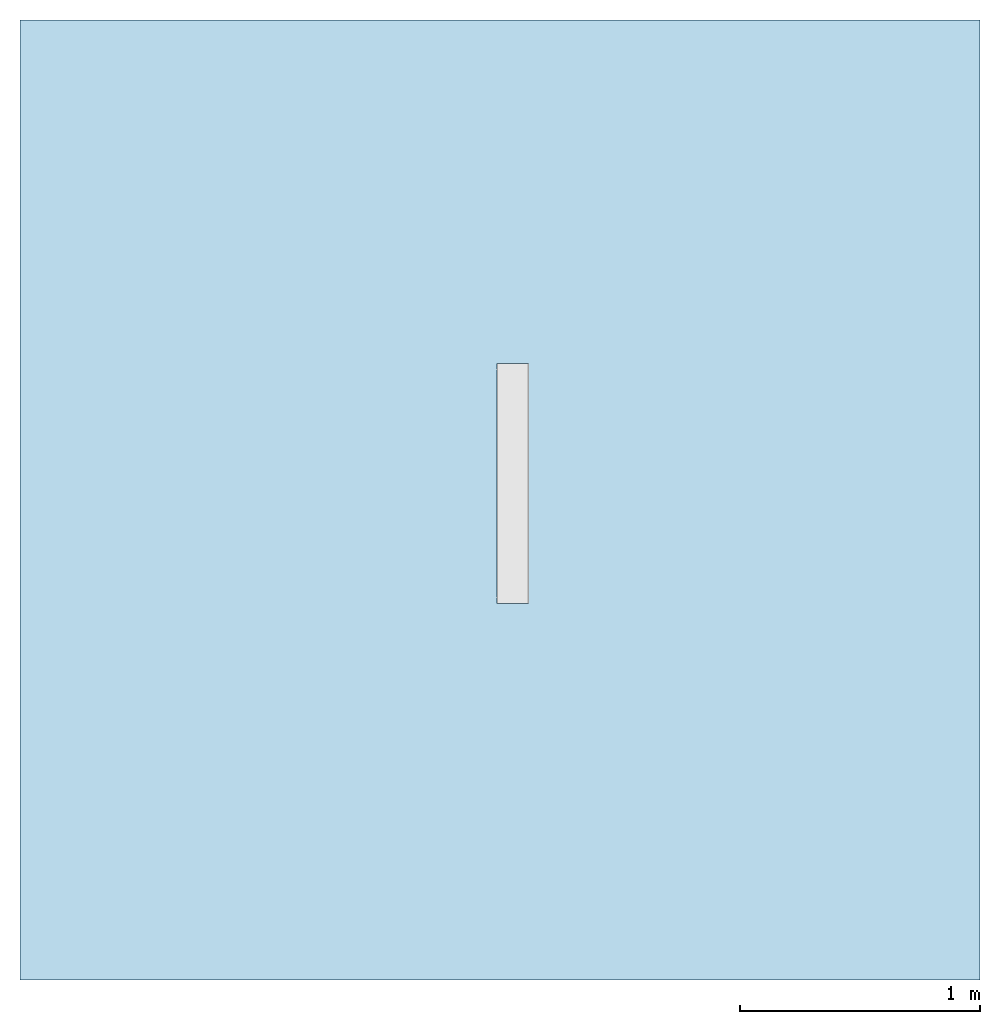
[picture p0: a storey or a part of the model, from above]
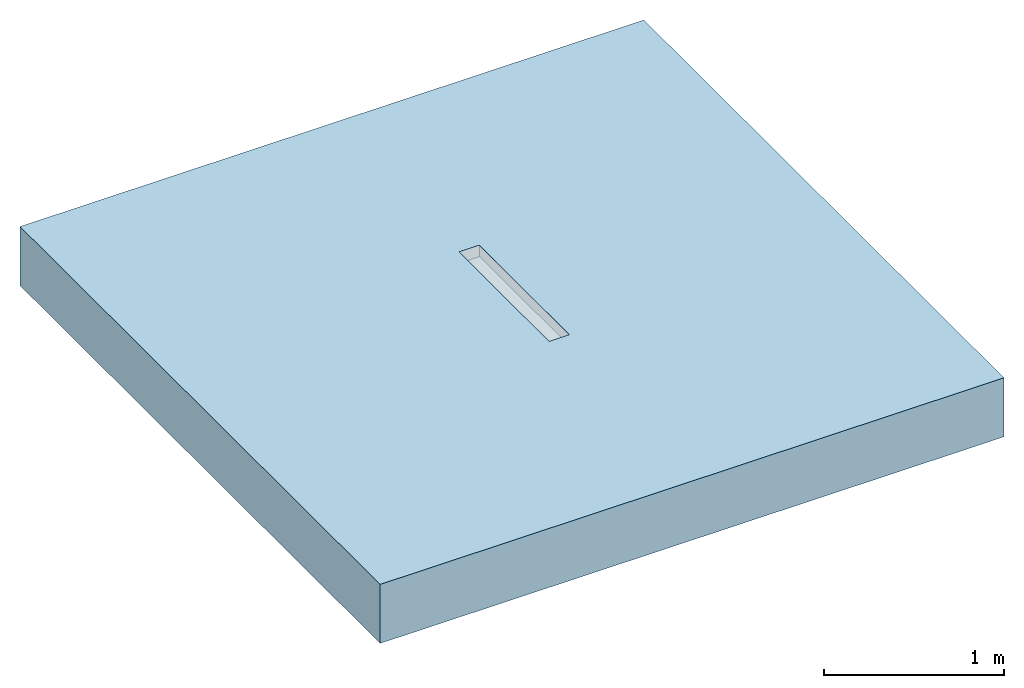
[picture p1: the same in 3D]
Properties of the parts of a building model (IFC2X3)

# File
Description: ViewDefinition [CoordinationView]
File name: Project Number
Time: 2014-06-06T14:49:13
Written by: The EXPRESS Data Manager Version 5.01.0100.02.64mod : 6 Jun 2012
Made in: 20130308_1515(x64) - Exporter 2014.0.2013.0308 - Default UI
Comment: STEP Physical File produced by: The EXPRESS Data Manager Version 5.01.0100.02.64mod : 6 Jun 2012 * Module: EDMstepFileFactory/EDMstandAlone * Creation date: Fri Jun 06 14:49:13 2014 * Host: IN-BLR-PC-0010 * Database: C:\Users\palleri\AppData\Local\Temp\{F6729BFF-8705-4B80-A60D-7009C70806BE}\ifc * Database version: 5507 * Database creation date: Fri Jun 06 14:49:11 2014 * Schema: IFC2X3 * Model: DataRepository.ifc * Model creation date: Fri Jun 06 14:49:12 2014 * Header model: DataRepository.ifc_HeaderModel * Header model creation date: Fri Jun 06 14:49:12 2014 * EDMuser: sdai-user * EDMgroup: sdai-group * License ID and type: 5605 : Permanent license. Expiry date: * EDMstepFileFactory options: 020000

# IfcProject, Project Number
LongName: Project Name; Phase: Project Status

# IfcSite, Default
RefLatitude: 42, 21, 30, 344238; RefLongitude: -71, -3, -35, -194702; RefElevation: 0 mm

# IfcBuilding
Pset_BuildingCommon - NumberOfStoreys: 1
Other - Project Address: ## Street City, State Zip; Project Number: Project Number; Project Issue Date: Issue Date; Client Name: Owner; Project Name: Project Name; Project Status: Project Status

# IfcBuildingStorey, Level 1
LongName: Level 1; Elevation: 0 mm
Constraints - Elevation Base: Project Base Point; Elevation: 0 mm
Graphics - Line Pattern: Center; Symbol: M_Level Head - Circle: M_Level Head - Circle; Line Weight: 1; Symbol at End 2 Default: yes; Symbol at End 1 Default: no; Color: 0
Identity Data - Building Story: yes; Structural: no; Name: Level 1
Dimensions - Computation Height: 0 mm

# IfcFlowTerminal: 36943 - Adjustable Channel - Shallow Section - 1000mm LG - Invert Depth 55/77mm, ACO Freedeck Adjustable Height Channel Shallow Section Stainless Steel:36943 - Adjustable Channel - Shallow Section - 1000mm LG - Invert Depth 55/77mm:317948
In: Level 1
Material: Stainless Steel Grade 304
Identity Data - Mark: 29; E-mail Technical: abdtechnical@aco.co.uk; E-mail Sales: abdcommercial@aco.co.uk; Fax: +44 (0)1462 851490; Address: ACO Business Centre, Caxton Road, Bedford, MK41 0LF; Watermark1: This file is the property of ACO Technologies PLC; Telephone: +44 (0)1462 816666; Manufacturer: ACO Building Drainage; Watermark2: This file is water marked and users are prohibited to reproduce, adapt, distribute this information; Watermarked With: BIM Manager Premium Suite; Website: www.acobd.com; Watermarked By: www.acobd.com
Construction - 36954 - Grating - Plain Mesh - Stainless Steel 304 - 500mm long: no; End Plate Invert 1: no; 36955 - Grating - Plain Mesh - Stainless Steel 304 - 1000mm long: yes; 00272 - Grating - Slotted Grating - Stainless Steel 304 - 1000mm long: no; 00273 - Grating - Slotted Grating - Stainless Steel 304 - 500mm long: no; End Plate Invert 2: no
Other - Top Piece Void Height @ Invert 1: 31 mm; Height @ Invert 2 Min & Max: 77 mm; Height @ Invert 1 Min & Max: 77 mm; Top Piece Void Height @ Invert 2: 31 mm; Nos: 32
Constraints - Level: Level: Level 1; Moves With Nearby Elements: no
Phasing - Phase Created: New Construction
Dimensions - Height @ Invert 2 (55 -77mm): 77 mm; Height @ Invert 1 (55 -77mm): 77 mm; Grating End Length: 1000 mm; Channel End Length: -1000 mm
Pset_ManufacturerTypeInformation - Manufacturer: ACO Building Drainage
Model Properties - End Plate Product Code 36951: End Plate - Stainless Steel 304 for Invert Depth - 55/77mm - 0.1Kg; Grating Product Code 00273: Load Class A15 - Slotted Grating - 10 x 80mm Slot - Stainless Steel 304 - 500mm long - 1.0kg; Grating Product Code 36954: Load Class A15 - Mesh Grating - 14mm x 30mm Mesh - Stainless Steel 304 - 500mm long - 1.6kg; Grating Product Code 36955: Load Class A15 - Mesh Grating - 14mm x 30mm Mesh - Stainless Steel 304 - 1000mm long - 3.0kg; Grating Product Code 00272: Load Class A15 - Slotted Grating - 10 x 80mm Slot - Stainless Steel 304 - 1000mm long - 2.2kg
General - Channel Recycled Material Content: 60-70%; Product Standard: BS EN 1433:2002, CE marked; Channel Recyclable: Fully recyclable; Product Range: ACO Freedeck; Price: POA - contact ACO; Installation Guidelines: X:\Electronic Literature\ABD Electronic Literature\Roof and Balcony Drainage\ACO Freedeck Brochure.pdf; Weight (Kg): 4.9kg; Channel Material: Stainless Steel Grade 304; Product Type: Linear Deck Drainage System; Channel Colour: Mid Grey; Load Class: A15; Product Description: ACO Freedeck Adjustable Channel - Shallow Section; Dimensions (LxWxH): 1000 x 130 x 55/77; Product Code: 36943; Maintenance Guidelines: X:\Electronic Literature\ABD Electronic Literature\Roof and Balcony Drainage\ACO Freedeck Brochure.pdf; NBS Specification: NBS Section R10 Gravity Rainwater Drainage Systems, Subsection 365
Materials and Finishes - Material: Stainless Steel Grade 304

# IfcOpeningElement: Recess
In: Level 1
Constraints - Level: Level: Level 1; Height Offset From Level: 0 mm; Related to Mass: no; Room Bounding: yes
Dimensions - Perimeter: 16000 mm; Area: 16 m2; Thickness: 400 mm; Volume: 6.38981 m3
Phasing - Phase Created: New Construction
Structural - Enable Analytical Model: no; Structural: no
Analytical Properties - Heat Transfer Coefficient (U): 2.615; Thermal Resistance (R): 0.382409; Roughness: 1; Thermal mass: 604440; Absorptance: 0.1
Materials and Finishes - Structural Material: Concrete, Broom Finish
Construction - Default Thickness: 400 mm; Function: Interior
Graphics - Coarse Scale Fill Color: 0

# IfcSlab: Floor:Generic Floor - 400mm, Floor:Generic Floor - 400mm:193825
In: Level 1
PredefinedType: FLOOR; Material: Concrete, Broom Finish 400 mm
Constraints - Level: Level: Level 1; Height Offset From Level: 0 mm; Related to Mass: no; Room Bounding: yes
Dimensions - Perimeter: 16000 mm; Area: 16 m2; Thickness: 400 mm; Volume: 6.38981 m3
Phasing - Phase Created: New Construction
Structural - Enable Analytical Model: no; Structural: no
Pset_SlabCommon - Reference: Generic Floor - 400mm; IsExternal: no; LoadBearing: yes; ThermalTransmittance: 2.615 kg/K/s3
Analytical Properties - Heat Transfer Coefficient (U): 2.615; Thermal Resistance (R): 0.382409; Roughness: 1; Thermal mass: 604440; Absorptance: 0.1
Materials and Finishes - Structural Material: Concrete, Broom Finish
Construction - Default Thickness: 400 mm; Function: Interior
Graphics - Coarse Scale Fill Color: 0
